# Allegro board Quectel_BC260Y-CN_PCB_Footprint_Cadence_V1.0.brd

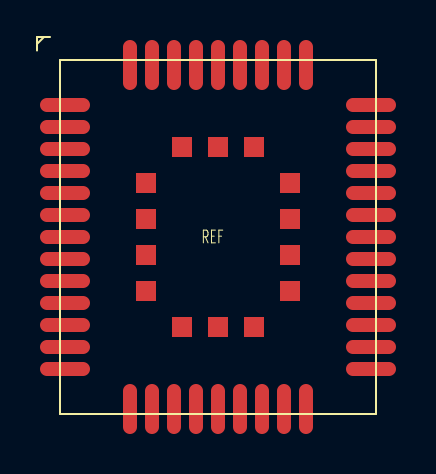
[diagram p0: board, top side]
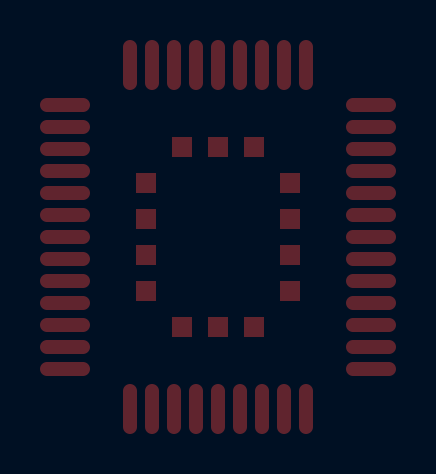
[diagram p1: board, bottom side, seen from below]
No outline. copper layers: TOP, BOTTOM. Coordinates in mm from the lowest, leftmost part position.

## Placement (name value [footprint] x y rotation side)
REF  -  [unnamed]  0 0 0 top

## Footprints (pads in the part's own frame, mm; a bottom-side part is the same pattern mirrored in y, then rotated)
unnamed
  oval 2.5x0.7 smd: 1(-7.65,6.6) 2(-7.65,5.5) 3(-7.65,4.4) 4(-7.65,3.3) 5(-7.65,2.2) 6(-7.65,1.1) 7(-7.65,0) 8(-7.65,-1.1) 9(-7.65,-2.2) 10(-7.65,-3.3) 11(-7.65,-4.4) 12(-7.65,-5.5) 13(-7.65,-6.6) 23(7.65,-6.6) 24(7.65,-5.5) 25(7.65,-4.4) 26(7.65,-3.3) 27(7.65,-2.2) 28(7.65,-1.1) 29(7.65,0) 30(7.65,1.1) 31(7.65,2.2) 32(7.65,3.3) 33(7.65,4.4) 34(7.65,5.5) 35(7.65,6.6)
  oval 0.7x2.5 smd: 14(-4.4,-8.6) 15(-3.3,-8.6) 16(-2.2,-8.6) 17(-1.1,-8.6) 18(0,-8.6) 19(1.1,-8.6) 20(2.2,-8.6) 21(3.3,-8.6) 22(4.4,-8.6) 36(4.4,8.6) 37(3.3,8.6) 38(2.2,8.6) 39(1.1,8.6) 40(0,8.6) 41(-1.1,8.6) 42(-2.2,8.6) 43(-3.3,8.6) 44(-4.4,8.6)
  rect 1x1 smd: 45(-3.6,2.7) 46(-3.6,0.9) 47(-3.6,-0.9) 48(-3.6,-2.7) 49(-1.8,-4.5) 50(0,-4.5) 51(1.8,-4.5) 52(3.6,-2.7) 53(3.6,-0.9) 54(3.6,0.9) 55(3.6,2.7) 56(1.8,4.5) 57(0,4.5) 58(-1.8,4.5)

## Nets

Pads without a net: REF 1 2 3 4 5 6 7 8 9 10 11 12 13 14 15 16 17 18 19 20 21 22 23 24 25 26 27 28 29 30 31 32 33 34 35 36 37 38 39 40 41 42 43 44 45 46 47 48 49 50 51 52 53 54 55 56 57 58
